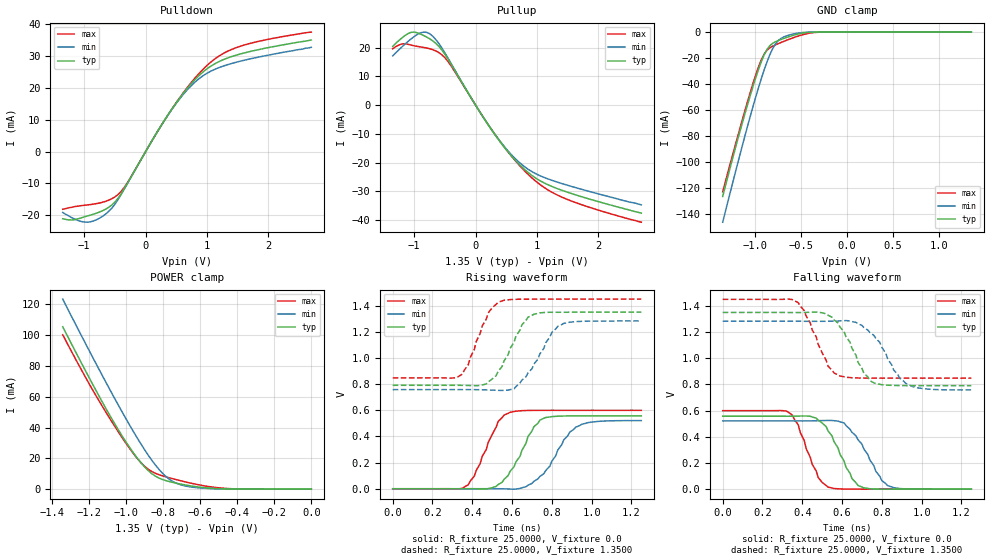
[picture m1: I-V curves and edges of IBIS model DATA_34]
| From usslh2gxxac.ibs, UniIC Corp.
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|When TDQS is enabled, NU_TDQS is a output with terminal resistance;
|When TDQS is disabled, NU_TDQS is a DM;
|   Model DATA_34
[Model]  DATA_34
Model_type I/O
Polarity   Non-Inverting
Enable   Active-High
Vinl =   0.54000000V
Vinh =   0.81000000V
Vmeas =   0.67500000V
Rref =   25.00000000
Vref =   0.67500000V
C_comp   1.6290pF   1.6100pF   1.6540pF
[Temperature Range]   25.0000   95.0000   0.0
[Voltage Range]   1.3500V   1.2830V   1.4500V
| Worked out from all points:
|   slope of the pulldown table from 0 to 0.203 V, typ, clamps not added: 30.6 ohm
|   slope of the pullup table from 0 to 0.203 V, typ, clamps not added: 29.9 ohm
|   GND clamp passes 1 mA (typ) near -0.50 V on its own axis
|   POWER clamp passes 1 mA (typ) near -0.58 V on its own axis
|   rising waveform, R_fixture 25.0000, V_fixture 0.0: 20-80 % time 118ps typ, 135ps min, 107ps max; typ from 0 V to 0.557 V
|   rising waveform, R_fixture 25.0000, V_fixture 1.3500: 20-80 % time 113ps typ, 123ps min, 93.4ps max; typ from 0.791 V to 1.35 V
|   falling waveform, R_fixture 25.0000, V_fixture 0.0: 20-80 % time 113ps typ, 123ps min, 92ps max; typ from 0.557 V to 0 V
|   falling waveform, R_fixture 25.0000, V_fixture 1.3500: 20-80 % time 116ps typ, 127ps min, 106ps max; typ from 1.35 V to 0.791 V
[Pulldown]
|Voltage   I(typ)   I(min)   I(max)
-1.35V    -21.1mA    -19.1mA    -18.1mA
-1.2V     -21.48mA   -20.8mA    -17.48mA
-950mV    -20.24mA   -22.17mA   -16.75mA
-600mV    -17.48mA   -18.77mA   -15.25mA
-350mV    -11.73mA   -11.85mA   -11.32mA
150mV     4.943mA    4.94mA     4.909mA
450mV     14mA       13.86mA    14.02mA
750mV     21.51mA    20.87mA    21.88mA
1V        26.03mA    24.64mA    27.09mA
1.25V     28.79mA    26.8mA     30.69mA
1.55V     30.74mA    28.48mA    33.18mA
2.7V      35.1mA     32.8mA     37.59mA
[Pullup]
|Voltage   I(typ)   I(min)   I(max)
-1.35V    20.4mA     17.1mA     19.6mA
-1.2V     23.38mA    20.25mA    21.28mA
-1.05V    25.31mA    23.05mA    20.88mA
-900mV    24.74mA    25.1mA     20.24mA
-750mV    23.1mA     24.86mA    19.62mA
-600mV    20.47mA    21.48mA    18.29mA
-450mV    16.03mA    16.38mA    15.2mA
250mV     -8.265mA   -8.209mA   -8.157mA
750mV     -21.44mA   -20.63mA   -21.8mA
1.05V     -26.3mA    -24.57mA   -27.64mA
1.4V      -29.59mA   -27.25mA   -31.96mA
2.7V      -37.6mA    -34.7mA    -40.73mA
[GND_clamp]
|Voltage   I(typ)   I(min)   I(max)
-1.35V    -126.6mA   -146.4mA   -123mA
-1.23V    -94.01mA   -112.8mA   -91.37mA
-1.14V    -70.71mA   -88.3mA    -68.32mA
-1.05V    -48.66mA   -64.66mA   -46.23mA
-960mV    -28.53mA   -42.51mA   -26.55mA
-900mV    -17.55mA   -29.16mA   -16.95mA
-840mV    -10.62mA   -17.72mA   -12.2mA
-780mV    -7.577mA   -9.433mA   -9.942mA
-720mV    -5.772mA   -5.033mA   -8.117mA
-540mV    -1.645mA   -864.3uA   -3.292mA
-330mV    -28.04uA   -10.8uA    -188.4uA
1.35V     3.66nA     11.73nA    27.08nA
[POWER_clamp]
|Voltage   I(typ)   I(min)   I(max)
-1.34V    105.5mA    123.5mA    100.3mA
-1.16V    63.99mA    81.44mA    60.61mA
-1.06V    42.52mA    58.94mA    40.95mA
-980mV    27.22mA    41.75mA    26.56mA
-920mV    17.45mA    29.69mA    17.42mA
-880mV    12.18mA    22.27mA    13mA
-840mV    8.415mA    15.63mA    10.28mA
-780mV    5.408mA    7.848mA    7.861mA
-700mV    3.206mA    2.693mA    5.332mA
-600mV    1.29mA     794.5uA    2.681mA
-420mV    69.47uA    44.47uA    238.7uA
0V        3.66nA     5.436nA    31.95nA
[Ramp]
| variable   typ   min   max
dV/dt_r  0.3343/0.1169n   0.3127/0.1346n   0.3598/99.9209p
dV/dt_f  0.3356/0.1137n   0.3152/0.1290n   0.3613/98.2845p
R_load = 25.0000
[Rising Waveform]
R_fixture= 25.0000
V_fixture= 0.0
V_fixture_min= 0.0
V_fixture_max= 0.0
|time   V(typ)   V(min)   V(max)
0s        0V         0V         0V
380ps     250uV      20.21uV    30.66mV
410ps     117.4uV    74.84uV    95.57mV
530ps     32.08mV    9.552uV    513.7mV
590ps     132.8mV    -2.345mV   584.5mV
710ps     474.8mV    56.97mV    599.1mV
760ps     539.1mV    115.7mV    599.5mV
860ps     556.1mV    373.5mV    599.6mV
920ps     557mV      470.3mV    599.6mV
1.25ns    557.2mV    521.1mV    599.6mV
[Rising Waveform]
R_fixture= 25.0000
V_fixture= 1.3500
V_fixture_min= 1.2830
V_fixture_max= 1.4500
|time   V(typ)   V(min)   V(max)
0s        790.7mV    757.6mV    847.8mV
350ps     790.5mV    757.7mV    876.5mV
380ps     789.5mV    757.7mV    948.2mV
480ps     816.6mV    755mV      1.344V
520ps     864.6mV    753mV      1.41V
560ps     977.9mV    752mV      1.441V
610ps     1.12V      763.8mV    1.448V
680ps     1.311V     884.7mV    1.449V
830ps     1.349V     1.242V     1.45V
1.25ns    1.35V      1.283V     1.45V
[Falling Waveform]
R_fixture= 25.0000
V_fixture= 0.0
V_fixture_min= 0.0
V_fixture_max= 0.0
|time   V(typ)   V(min)   V(max)
0s        557.2mV    521.1mV    599.6mV
350ps     557.3mV    521mV      566.3mV
380ps     558mV      520.9mV    490.9mV
480ps     527.4mV    523.2mV    90.02mV
530ps     444.9mV    524.9mV    15.71mV
610ps     216mV      506mV      935.2uV
650ps     80.92mV    434.4mV    178.7uV
710ps     9.833mV    305.7mV    19.12uV
830ps     108.3uV    26.34mV    0V
1.25ns    0V         0V         0V
[Falling Waveform]
R_fixture= 25.0000
V_fixture= 1.3500
V_fixture_min= 1.2830
V_fixture_max= 1.4500
|time   V(typ)   V(min)   V(max)
0s        1.35V      1.283V     1.45V
380ps     1.349V     1.283V     1.424V
440ps     1.351V     1.282V     1.271V
530ps     1.328V     1.283V     939.2mV
590ps     1.237V     1.286V     864.4mV
710ps     885.4mV    1.234V     848.3mV
760ps     812.2mV    1.175V     847.9mV
860ps     792.3mV    909.5mV    847.8mV
920ps     791mV      808mV      847.8mV
1.25ns    790.7mV    757.7mV    847.8mV
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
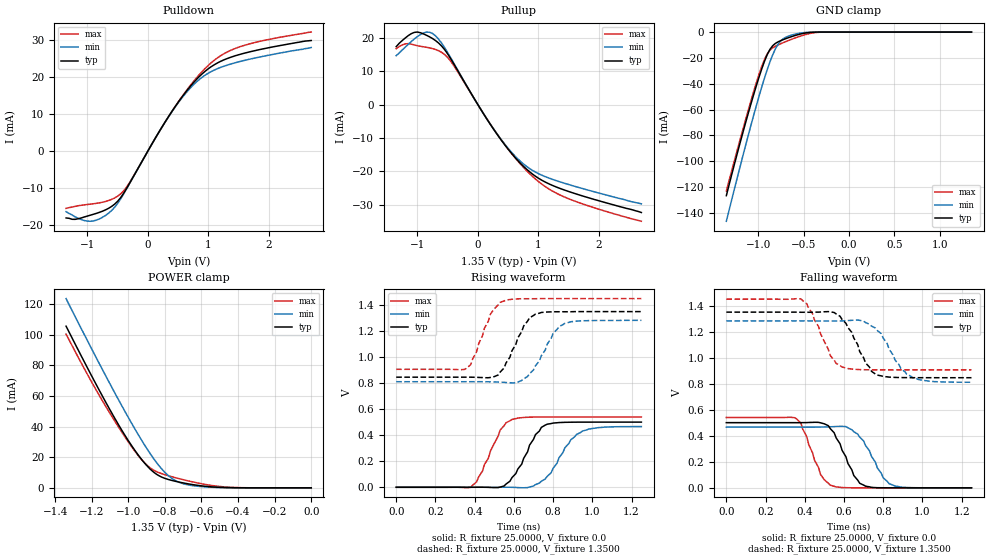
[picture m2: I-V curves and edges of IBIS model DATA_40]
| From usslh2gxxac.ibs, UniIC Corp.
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|   Model DATA_40
[Model]  DATA_40
Model_type I/O
Polarity   Non-Inverting
Enable   Active-High
Vinl =   0.54000000V
Vinh =   0.81000000V
Vmeas =   0.67500000V
Rref =   25.00000000
Vref =   0.67500000V
C_comp   1.6290pF   1.6100pF   1.6540pF
[Temperature Range]   25.0000   95.0000   0.0
[Voltage Range]   1.3500V   1.2830V   1.4500V
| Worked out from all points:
|   slope of the pulldown table from 0 to 0.203 V, typ, clamps not added: 35.6 ohm
|   slope of the pullup table from 0 to 0.203 V, typ, clamps not added: 34.8 ohm
|   GND clamp passes 1 mA (typ) near -0.50 V on its own axis
|   POWER clamp passes 1 mA (typ) near -0.58 V on its own axis
|   rising waveform, R_fixture 25.0000, V_fixture 0.0: 20-80 % time 102ps typ, 120ps min, 95.7ps max; typ from 0 V to 0.501 V
|   rising waveform, R_fixture 25.0000, V_fixture 1.3500: 20-80 % time 97.2ps typ, 102ps min, 85.6ps max; typ from 0.846 V to 1.35 V
|   falling waveform, R_fixture 25.0000, V_fixture 0.0: 20-80 % time 93ps typ, 104ps min, 82.9ps max; typ from 0.501 V to 0 V
|   falling waveform, R_fixture 25.0000, V_fixture 1.3500: 20-80 % time 103ps typ, 113ps min, 92.4ps max; typ from 1.35 V to 0.846 V
[Pulldown]
|Voltage   I(typ)   I(min)   I(max)
-1.35V    -18.1mA    -16.4mA    -15.5mA
-1.2V     -18.48mA   -17.8mA    -14.96mA
-950mV    -17.36mA   -19mA      -14.36mA
-600mV    -15mA      -16.12mA   -13.08mA
-350mV    -10.09mA   -10.2mA    -9.729mA
150mV     4.251mA    4.248mA    4.221mA
450mV     12.04mA    11.91mA    12.05mA
750mV     18.48mA    17.93mA    18.8mA
1V        22.35mA    21.14mA    23.26mA
1.25V     24.7mA     22.99mA    26.34mA
1.55V     26.36mA    24.42mA    28.46mA
2.7V      30mA       28.1mA     32.29mA
[Pullup]
|Voltage   I(typ)   I(min)   I(max)
-1.35V    17.4mA     14.7mA     16.8mA
-1.2V     20mA       17.25mA    18.24mA
-1.05V    21.68mA    19.73mA    17.91mA
-900mV    21.23mA    21.49mA    17.36mA
-750mV    19.83mA    21.34mA    16.82mA
-600mV    17.59mA    18.47mA    15.7mA
-450mV    13.79mA    14.09mA    13.06mA
250mV     -7.107mA   -7.058mA   -7.014mA
750mV     -18.41mA   -17.72mA   -18.73mA
1.05V     -22.57mA   -21.08mA   -23.73mA
1.4V      -25.38mA   -23.37mA   -27.42mA
2.7V      -32.3mA    -29.7mA    -34.93mA
[GND_clamp]
|Voltage   I(typ)   I(min)   I(max)
-1.35V    -126.6mA   -146.4mA   -123mA
-1.23V    -94.01mA   -112.8mA   -91.37mA
-1.14V    -70.71mA   -88.3mA    -68.32mA
-1.05V    -48.66mA   -64.66mA   -46.23mA
-960mV    -28.53mA   -42.51mA   -26.55mA
-900mV    -17.55mA   -29.16mA   -16.95mA
-840mV    -10.62mA   -17.72mA   -12.2mA
-780mV    -7.577mA   -9.433mA   -9.942mA
-720mV    -5.772mA   -5.033mA   -8.117mA
-540mV    -1.645mA   -864.3uA   -3.292mA
-330mV    -28.04uA   -10.8uA    -188.4uA
1.35V     3.66nA     11.73nA    27.08nA
[POWER_clamp]
|Voltage   I(typ)   I(min)   I(max)
-1.34V    105.5mA    123.5mA    100.3mA
-1.16V    63.99mA    81.44mA    60.61mA
-1.06V    42.52mA    58.94mA    40.95mA
-980mV    27.22mA    41.75mA    26.56mA
-920mV    17.45mA    29.69mA    17.42mA
-880mV    12.18mA    22.27mA    13mA
-840mV    8.415mA    15.63mA    10.28mA
-780mV    5.408mA    7.848mA    7.861mA
-700mV    3.206mA    2.693mA    5.332mA
-600mV    1.29mA     794.5uA    2.681mA
-420mV    69.47uA    44.47uA    238.7uA
0V        3.66nA     5.436nA    31.95nA
[Ramp]
| variable   typ   min   max
dV/dt_r  0.3005/0.1058n   0.2799/0.1203n   0.3242/93.0091p
dV/dt_f  0.3023/0.1041n   0.2831/0.1145n   0.3261/91.8068p
R_load = 25.0000
[Rising Waveform]
R_fixture= 25.0000
V_fixture= 0.0
V_fixture_min= 0.0
V_fixture_max= 0.0
|time   V(typ)   V(min)   V(max)
0s        0V         0V         0V
380ps     95.35uV    -9.554uV   -413.5uV
440ps     330.8uV    55.67uV    125.3mV
530ps     1.559mV    374.3uV    439.9mV
590ps     73.89mV    -392.8uV   521mV
710ps     404.5mV    19.98mV    539.7mV
770ps     484.8mV    84.21mV    540.3mV
890ps     500.1mV    365.1mV    540.3mV
950ps     500.7mV    432.1mV    540.3mV
1.25ns    500.8mV    466.5mV    540.3mV
[Rising Waveform]
R_fixture= 25.0000
V_fixture= 1.3500
V_fixture_min= 1.2830
V_fixture_max= 1.4500
|time   V(typ)   V(min)   V(max)
0s        846.1mV    811.2mV    906.5mV
350ps     846.3mV    811.2mV    906.3mV
380ps     846.1mV    811.3mV    942.6mV
480ps     844.1mV    810.3mV    1.329V
560ps     955.6mV    805.1mV    1.439V
650ps     1.24V      834mV      1.449V
710ps     1.331V     934mV      1.449V
800ps     1.349V     1.183V     1.45V
860ps     1.349V     1.26V      1.45V
1.25ns    1.35V      1.283V     1.45V
[Falling Waveform]
R_fixture= 25.0000
V_fixture= 0.0
V_fixture_min= 0.0
V_fixture_max= 0.0
|time   V(typ)   V(min)   V(max)
0s        500.8mV    466.5mV    540.3mV
350ps     500.7mV    466.5mV    538.4mV
380ps     500.7mV    466.4mV    498.2mV
480ps     499.8mV    467.1mV    103.9mV
560ps     383.6mV    471.3mV    6.777mV
650ps     94.15mV    431.4mV    277.6uV
710ps     12.71mV    324.5mV    32.69uV
800ps     404.9uV    76.66mV    0V
860ps     61.5uV     13.66mV    0V
1.25ns    0V         0V         0V
[Falling Waveform]
R_fixture= 25.0000
V_fixture= 1.3500
V_fixture_min= 1.2830
V_fixture_max= 1.4500
|time   V(typ)   V(min)   V(max)
0s        1.35V      1.283V     1.45V
380ps     1.349V     1.283V     1.452V
440ps     1.349V     1.283V     1.337V
530ps     1.353V     1.282V     1.016V
590ps     1.294V     1.283V     928.6mV
710ps     959.3mV    1.27V      907.3mV
770ps     866.2mV    1.209V     906.6mV
890ps     847.2mV    916.4mV    906.5mV
950ps     846.4mV    846.7mV    906.5mV
1.25ns    846.1mV    811.3mV    906.5mV
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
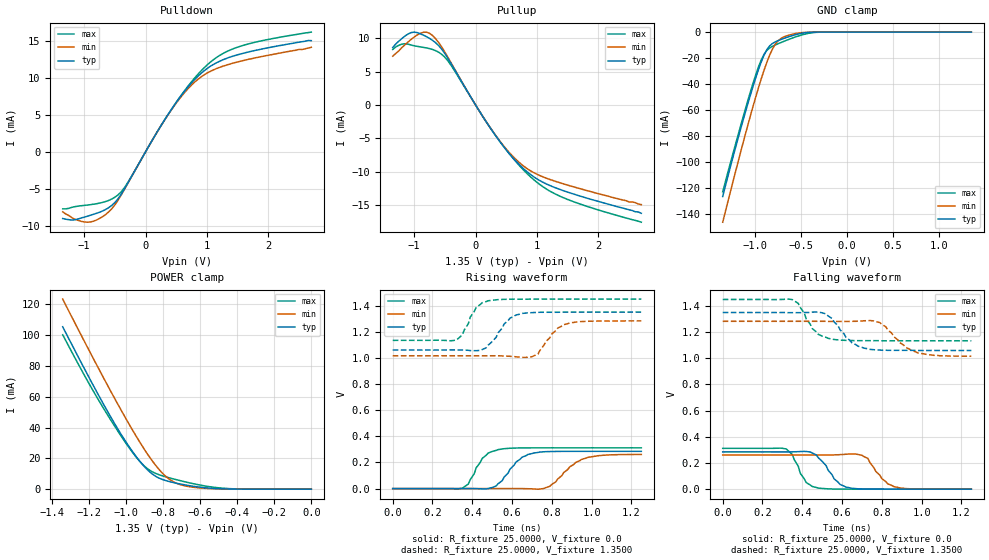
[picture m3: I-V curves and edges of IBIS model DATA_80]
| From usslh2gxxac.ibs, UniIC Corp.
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|   Model DATA_80
[Model]  DATA_80
Model_type I/O
Polarity   Non-Inverting
Enable   Active-High
Vinl =   0.54000000V
Vinh =   0.81000000V
Vmeas =   0.67500000V
Rref =   25.00000000
Vref =   0.67500000V
C_comp   1.6290pF   1.6100pF   1.6540pF
[Temperature Range]   25.0000   95.0000   0.0
[Voltage Range]   1.3500V   1.2830V   1.4500V
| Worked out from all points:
|   slope of the pulldown table from 0 to 0.203 V, typ, clamps not added: 70.5 ohm
|   slope of the pullup table from 0 to 0.203 V, typ, clamps not added: 69 ohm
|   GND clamp passes 1 mA (typ) near -0.50 V on its own axis
|   POWER clamp passes 1 mA (typ) near -0.58 V on its own axis
|   rising waveform, R_fixture 25.0000, V_fixture 0.0: 20-80 % time 95.1ps typ, 114ps min, 77.4ps max; typ from 0 V to 0.285 V
|   rising waveform, R_fixture 25.0000, V_fixture 1.3500: 20-80 % time 88.7ps typ, 85.8ps min, 64.4ps max; typ from 1.06 V to 1.35 V
|   falling waveform, R_fixture 25.0000, V_fixture 0.0: 20-80 % time 88.5ps typ, 85ps min, 62.1ps max; typ from 0.285 V to 0 V
|   falling waveform, R_fixture 25.0000, V_fixture 1.3500: 20-80 % time 95ps typ, 116ps min, 82ps max; typ from 1.35 V to 1.06 V
[Pulldown]
|Voltage   I(typ)   I(min)   I(max)
-1.35V    -9mA       -8.1mA     -7.7mA
-1.2V     -9.22mA    -8.9mA     -7.49mA
-950mV    -8.7mA     -9.5mA     -7.19mA
-800mV    -8.305mA   -9.21mA    -7.01mA
-600mV    -7.532mA   -8.104mA   -6.562mA
-350mV    -5.095mA   -5.151mA   -4.906mA
150mV     2.146mA    2.145mA    2.131mA
450mV     6.069mA    6.003mA    6.077mA
750mV     9.3mA      9.014mA    9.466mA
1V        11.22mA    10.61mA    11.69mA
1.5V      13.09mA    12.12mA    14.12mA
2.7V      15mA       14.1mA     16.15mA
[Pullup]
|Voltage   I(typ)   I(min)   I(max)
-1.35V    8.6mA      7.3mA      8.3mA
-1.2V     9.94mA     8.59mA     9.1mA
-1.05V    10.82mA    9.81mA     8.97mA
-900mV    10.64mA    10.72mA    8.69mA
-750mV    9.959mA    10.72mA    8.43mA
-600mV    8.86mA     9.316mA    7.879mA
-450mV    6.969mA    7.125mA    6.59mA
250mV     -3.587mA   -3.562mA   -3.54mA
750mV     -9.264mA   -8.906mA   -9.428mA
1.05V     -11.33mA   -10.57mA   -11.92mA
1.4V      -12.72mA   -11.71mA   -13.75mA
2.7V      -16.2mA    -14.9mA    -17.53mA
[GND_clamp]
|Voltage   I(typ)   I(min)   I(max)
-1.35V    -126.6mA   -146.4mA   -123mA
-1.23V    -94.01mA   -112.8mA   -91.37mA
-1.14V    -70.71mA   -88.3mA    -68.32mA
-1.05V    -48.66mA   -64.66mA   -46.23mA
-960mV    -28.53mA   -42.51mA   -26.55mA
-900mV    -17.55mA   -29.16mA   -16.95mA
-840mV    -10.62mA   -17.72mA   -12.2mA
-780mV    -7.577mA   -9.433mA   -9.942mA
-720mV    -5.772mA   -5.033mA   -8.117mA
-540mV    -1.645mA   -864.3uA   -3.292mA
-330mV    -28.04uA   -10.8uA    -188.4uA
1.35V     3.66nA     11.73nA    27.08nA
[POWER_clamp]
|Voltage   I(typ)   I(min)   I(max)
-1.34V    105.5mA    123.5mA    100.3mA
-1.16V    63.99mA    81.44mA    60.61mA
-1.06V    42.52mA    58.94mA    40.95mA
-980mV    27.22mA    41.75mA    26.56mA
-920mV    17.45mA    29.69mA    17.42mA
-880mV    12.18mA    22.27mA    13mA
-840mV    8.415mA    15.63mA    10.28mA
-780mV    5.408mA    7.848mA    7.861mA
-700mV    3.206mA    2.693mA    5.332mA
-600mV    1.29mA     794.5uA    2.681mA
-420mV    69.47uA    44.47uA    238.7uA
0V        3.66nA     5.436nA    31.95nA
[Ramp]
| variable   typ   min   max
dV/dt_r  0.1711/95.8702p   0.1568/0.1150n   0.1871/74.5281p
dV/dt_f  0.1740/97.5000p   0.1602/0.1134n   0.1896/78.8115p
R_load = 25.0000
[Rising Waveform]
R_fixture= 25.0000
V_fixture= 0.0
V_fixture_min= 0.0
V_fixture_max= 0.0
|time   V(typ)   V(min)   V(max)
0s        0V         0V         0V
350ps     147.1uV    0V         2.732mV
380ps     308.3uV    -1.668uV   34.42mV
450ps     -2.449mV   -13.34uV   231.4mV
530ps     37.36mV    89.21uV    298.3mV
620ps     203.4mV    449.6uV    310.4mV
710ps     272.5mV    -3.187mV   311.8mV
790ps     283.4mV    17.6mV     311.9mV
980ps     285mV      238.6mV    311.9mV
1.25ns    285.1mV    261.3mV    311.9mV
[Rising Waveform]
R_fixture= 25.0000
V_fixture= 1.3500
V_fixture_min= 1.2830
V_fixture_max= 1.4500
|time   V(typ)   V(min)   V(max)
0s        1.06V      1.016V     1.134V
320ps     1.061V     1.016V     1.136V
350ps     1.06V      1.016V     1.176V
420ps     1.055V     1.016V     1.387V
480ps     1.097V     1.016V     1.437V
590ps     1.304V     1.012V     1.449V
650ps     1.34V      1.004V     1.449V
730ps     1.348V     1.028V     1.45V
860ps     1.35V      1.254V     1.45V
1.25ns    1.35V      1.283V     1.45V
[Falling Waveform]
R_fixture= 25.0000
V_fixture= 0.0
V_fixture_min= 0.0
V_fixture_max= 0.0
|time   V(typ)   V(min)   V(max)
0s        285.1mV    261.4mV    311.9mV
320ps     284.8mV    261.4mV    307.1mV
350ps     285.2mV    261.4mV    264.4mV
420ps     288mV      261.3mV    50.49mV
480ps     241.1mV    261mV      8.563mV
620ps     15.58mV    267.3mV    160.2uV
730ps     785.6uV    235.2mV    6.833uV
800ps     64.2uV     80.46mV    0V
860ps     11.7uV     19.72mV    0V
1.25ns    0V         0V         0V
[Falling Waveform]
R_fixture= 25.0000
V_fixture= 1.3500
V_fixture_min= 1.2830
V_fixture_max= 1.4500
|time   V(typ)   V(min)   V(max)
0s        1.35V      1.283V     1.45V
350ps     1.349V     1.283V     1.449V
380ps     1.349V     1.283V     1.42V
450ps     1.353V     1.283V     1.228V
500ps     1.348V     1.283V     1.17V
550ps     1.305V     1.282V     1.147V
650ps     1.118V     1.283V     1.136V
760ps     1.066V     1.286V     1.135V
980ps     1.06V      1.042V     1.134V
1.25ns    1.06V      1.016V     1.134V
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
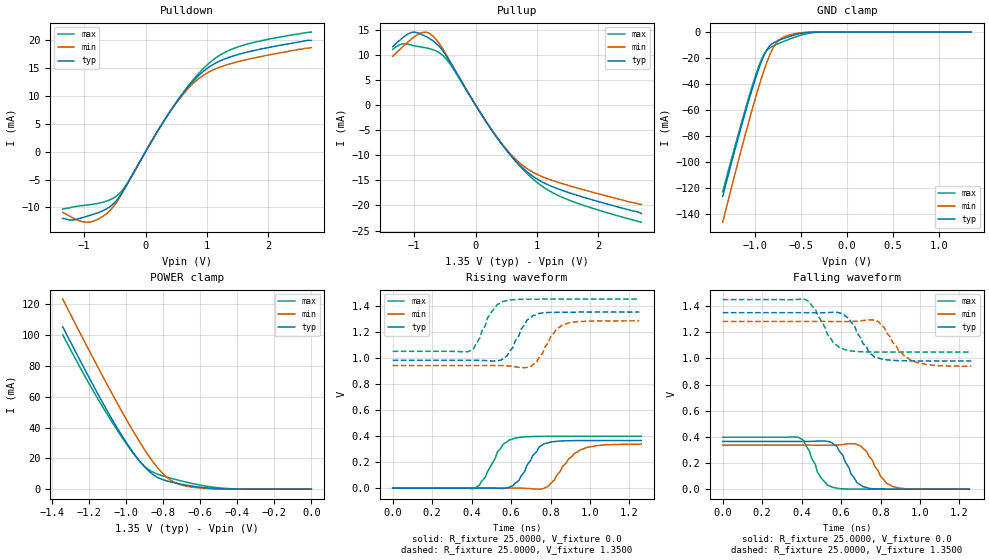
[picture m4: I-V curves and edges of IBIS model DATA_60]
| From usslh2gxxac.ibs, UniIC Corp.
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|   Model DATA_60
[Model]  DATA_60
Model_type I/O
Polarity   Non-Inverting
Enable   Active-High
Vinl =   0.54000000V
Vinh =   0.81000000V
Vmeas =   0.67500000V
Rref =   25.00000000
Vref =   0.67500000V
C_comp   1.6290pF   1.6100pF   1.6540pF
[Temperature Range]   25.0000   95.0000   0.0
[Voltage Range]   1.3500V   1.2830V   1.4500V
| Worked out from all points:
|   slope of the pulldown table from 0 to 0.203 V, typ, clamps not added: 53.1 ohm
|   slope of the pullup table from 0 to 0.203 V, typ, clamps not added: 51.9 ohm
|   GND clamp passes 1 mA (typ) near -0.50 V on its own axis
|   POWER clamp passes 1 mA (typ) near -0.58 V on its own axis
|   rising waveform, R_fixture 25.0000, V_fixture 0.0: 20-80 % time 89.5ps typ, 106ps min, 85.6ps max; typ from 0 V to 0.365 V
|   rising waveform, R_fixture 25.0000, V_fixture 1.3500: 20-80 % time 80.5ps typ, 82.1ps min, 79.3ps max; typ from 0.98 V to 1.35 V
|   falling waveform, R_fixture 25.0000, V_fixture 0.0: 20-80 % time 81.1ps typ, 84.2ps min, 74ps max; typ from 0.365 V to 0 V
|   falling waveform, R_fixture 25.0000, V_fixture 1.3500: 20-80 % time 86.7ps typ, 107ps min, 85.1ps max; typ from 1.35 V to 0.98 V
[Pulldown]
|Voltage   I(typ)   I(min)   I(max)
-1.35V    -12mA      -10.9mA    -10.3mA
-1.2V     -12.29mA   -11.8mA    -9.98mA
-950mV    -11.59mA   -12.67mA   -9.58mA
-600mV    -10.03mA   -10.79mA   -8.732mA
-350mV    -6.771mA   -6.844mA   -6.524mA
150mV     2.852mA    2.85mA     2.832mA
450mV     8.069mA    7.982mA    8.079mA
750mV     12.37mA    12mA       12.59mA
1V        14.94mA    14.13mA    15.56mA
1.25V     16.49mA    15.34mA    17.6mA
1.55V     17.59mA    16.3mA     18.99mA
2.7V      20mA       18.7mA     21.49mA
[Pullup]
|Voltage   I(typ)   I(min)   I(max)
-1.35V    11.6mA     9.7mA      11.1mA
-1.2V     13.28mA    11.45mA    12.15mA
-1.05V    14.44mA    13.1mA     11.95mA
-900mV    14.18mA    14.31mA    11.58mA
-750mV    13.26mA    14.27mA    11.23mA
-600mV    11.78mA    12.39mA    10.5mA
-450mV    9.259mA    9.464mA    8.761mA
250mV     -4.768mA   -4.734mA   -4.705mA
750mV     -12.33mA   -11.85mA   -12.54mA
1.05V     -15.08mA   -14.08mA   -15.87mA
1.35V     -16.72mA   -15.41mA   -18.04mA
2.7V      -21.6mA    -19.8mA    -23.33mA
[GND_clamp]
|Voltage   I(typ)   I(min)   I(max)
-1.35V    -126.6mA   -146.4mA   -123mA
-1.23V    -94.01mA   -112.8mA   -91.37mA
-1.14V    -70.71mA   -88.3mA    -68.32mA
-1.05V    -48.66mA   -64.66mA   -46.23mA
-960mV    -28.53mA   -42.51mA   -26.55mA
-900mV    -17.55mA   -29.16mA   -16.95mA
-840mV    -10.62mA   -17.72mA   -12.2mA
-780mV    -7.577mA   -9.433mA   -9.942mA
-720mV    -5.772mA   -5.033mA   -8.117mA
-540mV    -1.645mA   -864.3uA   -3.292mA
-330mV    -28.04uA   -10.8uA    -188.4uA
1.35V     3.66nA     11.73nA    27.08nA
[POWER_clamp]
|Voltage   I(typ)   I(min)   I(max)
-1.34V    105.5mA    123.5mA    100.3mA
-1.16V    63.99mA    81.44mA    60.61mA
-1.06V    42.52mA    58.94mA    40.95mA
-980mV    27.22mA    41.75mA    26.56mA
-920mV    17.45mA    29.69mA    17.42mA
-880mV    12.18mA    22.27mA    13mA
-840mV    8.415mA    15.63mA    10.28mA
-780mV    5.408mA    7.848mA    7.861mA
-700mV    3.206mA    2.693mA    5.332mA
-600mV    1.29mA     794.5uA    2.681mA
-420mV    69.47uA    44.47uA    238.7uA
0V        3.66nA     5.436nA    31.95nA
[Ramp]
| variable   typ   min   max
dV/dt_r  0.2191/91.3875p   0.2020/0.1080n   0.2384/81.1256p
dV/dt_f  0.2217/91.5243p   0.2057/0.1059n   0.2406/82.7241p
R_load = 25.0000
[Rising Waveform]
R_fixture= 25.0000
V_fixture= 0.0
V_fixture_min= 0.0
V_fixture_max= 0.0
|time   V(typ)   V(min)   V(max)
0s        0V         0V         0V
410ps     26.87uV    -4.966uV   -4.273mV
470ps     313.1uV    -20.2uV    84.25mV
530ps     -1.175mV   82.15uV    275.2mV
580ps     524.6uV    386.4uV    355.9mV
640ps     59.46mV    491.2uV    388.2mV
710ps     251.2mV    -5.999mV   396mV
760ps     332.9mV    -5.287mV   397mV
950ps     364.8mV    292.9mV    397.3mV
1.26ns    365.2mV    337.3mV    397.3mV
[Rising Waveform]
R_fixture= 25.0000
V_fixture= 1.3500
V_fixture_min= 1.2830
V_fixture_max= 1.4500
|time   V(typ)   V(min)   V(max)
0s        980.5mV    940mV      1.049V
390ps     980.7mV    940mV      1.052V
440ps     980.1mV    940.1mV    1.148V
500ps     975.5mV    940.5mV    1.35V
590ps     1.044V     936.3mV    1.442V
680ps     1.288V     925.9mV    1.449V
740ps     1.339V     998.6mV    1.449V
800ps     1.348V     1.162V     1.45V
860ps     1.349V     1.251V     1.45V
1.25ns    1.35V      1.283V     1.45V
[Falling Waveform]
R_fixture= 25.0000
V_fixture= 0.0
V_fixture_min= 0.0
V_fixture_max= 0.0
|time   V(typ)   V(min)   V(max)
0s        365.2mV    336.7mV    397.3mV
380ps     365.1mV    336.7mV    398.2mV
410ps     365mV      336.7mV    373.2mV
500ps     368.5mV    336.2mV    82.96mV
560ps     345.3mV    336.8mV    12.1mV
680ps     50.01mV    341.2mV    269.9uV
710ps     20.31mV    312.6mV    103.9uV
800ps     868uV      97.17mV    3.253uV
860ps     145.1uV    20.6mV     0V
1.25ns    0V         3.694uV    0V
[Falling Waveform]
R_fixture= 25.0000
V_fixture= 1.3500
V_fixture_min= 1.2830
V_fixture_max= 1.4500
|time   V(typ)   V(min)   V(max)
0s        1.35V      1.283V     1.45V
420ps     1.35V      1.283V     1.449V
470ps     1.349V     1.283V     1.375V
590ps     1.349V     1.282V     1.084V
640ps     1.306V     1.282V     1.06V
760ps     1.022V     1.294V     1.049V
820ps     992.3mV    1.233V     1.049V
890ps     982.8mV    1.064V     1.049V
950ps     981.1mV    988.9mV    1.049V
1.26ns    980.5mV    940.1mV    1.049V
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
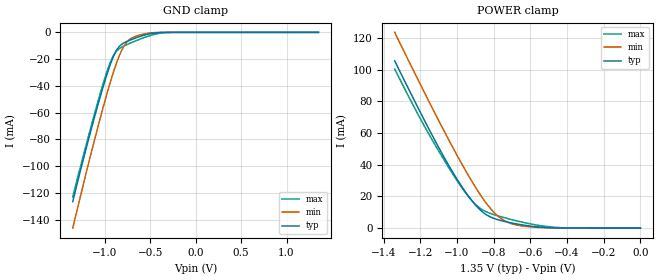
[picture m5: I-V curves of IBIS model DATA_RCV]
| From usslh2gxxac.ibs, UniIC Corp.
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|   Model DATA_RCV
[Model]  DATA_RCV
Model_type Input
Vinl =   0.54000000V
Vinh =   0.81000000V
C_comp   1.6290pF   1.6100pF   1.6540pF
[Temperature Range]   25.0000   95.0000   0.0
[Voltage Range]   1.3500V   1.2830V   1.4500V
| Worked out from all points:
|   GND clamp passes 1 mA (typ) near -0.50 V on its own axis
|   POWER clamp passes 1 mA (typ) near -0.58 V on its own axis
[GND_clamp]
|Voltage   I(typ)   I(min)   I(max)
-1.35V    -126.6mA   -146.4mA   -123mA
-1.23V    -94.01mA   -112.8mA   -91.37mA
-1.14V    -70.71mA   -88.3mA    -68.32mA
-1.05V    -48.66mA   -64.66mA   -46.23mA
-960mV    -28.53mA   -42.51mA   -26.55mA
-900mV    -17.55mA   -29.16mA   -16.95mA
-840mV    -10.62mA   -17.72mA   -12.2mA
-780mV    -7.577mA   -9.433mA   -9.942mA
-720mV    -5.772mA   -5.033mA   -8.117mA
-540mV    -1.645mA   -864.3uA   -3.292mA
-330mV    -28.04uA   -10.8uA    -188.4uA
1.35V     3.66nA     11.73nA    27.08nA
[POWER_clamp]
|Voltage   I(typ)   I(min)   I(max)
-1.34V    105.5mA    123.5mA    100.3mA
-1.16V    63.99mA    81.44mA    60.61mA
-1.06V    42.52mA    58.94mA    40.95mA
-980mV    27.22mA    41.75mA    26.56mA
-920mV    17.45mA    29.69mA    17.42mA
-880mV    12.18mA    22.27mA    13mA
-840mV    8.415mA    15.63mA    10.28mA
-780mV    5.408mA    7.848mA    7.861mA
-700mV    3.206mA    2.693mA    5.332mA
-600mV    1.29mA     794.5uA    2.681mA
-420mV    69.47uA    44.47uA    238.7uA
0V        3.66nA     5.436nA    31.95nA
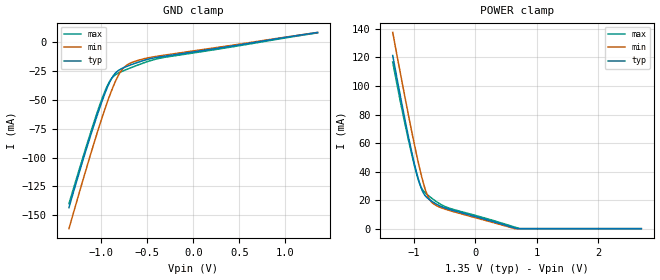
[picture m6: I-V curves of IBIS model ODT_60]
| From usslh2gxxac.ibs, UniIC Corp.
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|   Model ODT_60
[Model]  ODT_60
Model_type Input
Vinl =   0.54000000V
Vinh =   0.81000000V
C_comp   1.6290pF   1.6100pF   1.6540pF
[Temperature Range]   25.0000   95.0000   0.0
[Voltage Range]   1.3500V   1.2800V   1.4500V
[GND_clamp]
|Voltage   I(typ)   I(min)   I(max)
-1.35V    -143.4mA   -161.6mA   -140mA
-1.23V    -110.7mA   -128.2mA   -108.1mA
-1.14V    -87.26mA   -103.8mA   -84.75mA
-1.05V    -64.91mA   -80.22mA   -62.44mA
-960mV    -44.49mA   -58.01mA   -42.55mA
-900mV    -33.31mA   -44.54mA   -32.81mA
-840mV    -26.18mA   -32.93mA   -27.9mA
-780mV    -22.93mA   -24.4mA    -25.49mA
-720mV    -20.89mA   -19.73mA   -23.48mA
-570mV    -16.6mA    -15.05mA   -18.83mA
-330mV    -12.29mA   -11.4mA    -13.35mA
1.35V     8.47mA     8.53mA     8.122mA
[POWER_clamp]
|Voltage   I(typ)   I(min)   I(max)
-1.34V    121.4mA    137.6mA    116.8mA
-1.22V    94mA       110mA      90.09mA
-1.12V    72.01mA    87.54mA    69.28mA
-1.02V    51.59mA    65.83mA    50.06mA
-940mV    37.36mA    49.47mA    36.55mA
-880mV    28.83mA    38.26mA    29.22mA
-800mV    22.5mA     26.06mA    24.63mA
-740mV    20.27mA    20.35mA    22.47mA
-680mV    18.51mA    17.5mA     20.49mA
-420mV    13.53mA    12.79mA    14.36mA
675mV     0A         NA         NA
2.7V      0A         0A         0A
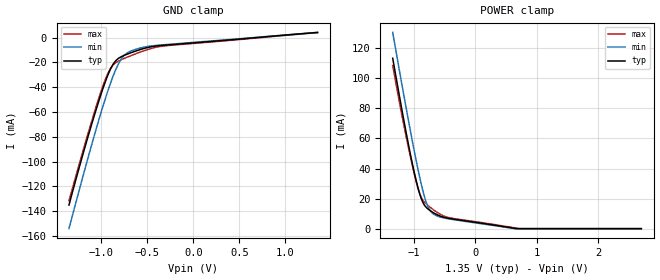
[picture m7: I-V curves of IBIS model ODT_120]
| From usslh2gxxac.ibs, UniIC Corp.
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|   Model ODT_120
[Model]  ODT_120
Model_type Input
Vinl =   0.54000000V
Vinh =   0.81000000V
C_comp   1.6290pF   1.6100pF   1.6540pF
[Temperature Range]   25.0000   95.0000   0.0
[Voltage Range]   1.3500V   1.2830V   1.4500V
[GND_clamp]
|Voltage   I(typ)   I(min)   I(max)
-1.35V    -135mA     -154mA     -131.5mA
-1.14V    -78.99mA   -96.1mA    -76.54mA
-1.02V    -49.74mA   -64.88mA   -47.34mA
-960mV    -36.51mA   -50.3mA    -34.55mA
-900mV    -25.43mA   -36.89mA   -24.88mA
-870mV    -21.31mA   -30.83mA   -21.92mA
-840mV    -18.4mA    -25.37mA   -20.05mA
-780mV    -15.26mA   -16.96mA   -17.72mA
-720mV    -13.34mA   -12.42mA   -15.8mA
-570mV    -9.41mA    -8.197mA   -11.43mA
-330mV    -6.169mA   -5.742mA   -6.779mA
1.35V     4.238mA    4.275mA    4.063mA
[POWER_clamp]
|Voltage   I(typ)   I(min)   I(max)
-1.34V    113.4mA    130.6mA    108.6mA
-1.22V    85.77mA    102.7mA    81.7mA
-1.12V    63.6mA     79.97mA    60.91mA
-1.02V    43.09mA    58.06mA    41.81mA
-940mV    28.93mA    41.56mA    28.38mA
-860mV    18.38mA    26.87mA    19.55mA
-800mV    14.34mA    18.1mA     16.6mA
-740mV    12.25mA    12.5mA     14.51mA
-680mV    10.64mA    9.841mA    12.63mA
-420mV    6.809mA    6.453mA    7.306mA
675mV     0A         NA         NA
2.7V      0A         0A         0A
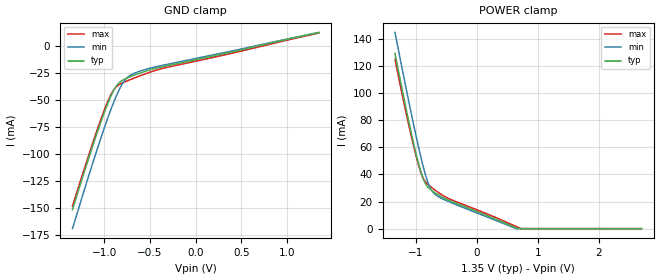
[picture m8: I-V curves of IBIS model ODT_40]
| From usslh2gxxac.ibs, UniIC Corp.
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|   Model ODT_40
[Model]  ODT_40
Model_type Input
Vinl =   0.54000000V
Vinh =   0.81000000V
C_comp   1.6290pF   1.6100pF   1.6540pF
[Temperature Range]   25.0000   95.0000   0.0
[Voltage Range]   1.3500V   1.2830V   1.4500V
[GND_clamp]
|Voltage   I(typ)   I(min)   I(max)
-1.35V    -151.8mA   -169.3mA   -148.5mA
-1.2V     -111.1mA   -127.9mA   -108.5mA
-1.11V    -87.88mA   -103.7mA   -85.33mA
-1.02V    -65.87mA   -80.5mA    -63.46mA
-960mV    -52.45mA   -65.86mA   -50.53mA
-900mV    -41.18mA   -52.33mA   -40.72mA
-870mV    -36.95mA   -46.18mA   -37.69mA
-810mV    -31.97mA   -35.83mA   -34.38mA
-750mV    -29.46mA   -29.14mA   -32.18mA
-660mV    -26.49mA   -24.63mA   -29.13mA
-450mV    -20.72mA   -19.34mA   -22.69mA
1.35V     12.7mA     12.8mA     12.18mA
[POWER_clamp]
|Voltage   I(typ)   I(min)   I(max)
-1.34V    129.3mA    144.8mA    125mA
-1.12V    80.44mA    95.24mA    77.65mA
-1.02V    60.08mA    73.74mA    58.31mA
-940mV    45.77mA    57.5mA     44.7mA
-880mV    37.14mA    46.35mA    37.32mA
-840mV    33.15mA    39.73mA    34.48mA
-800mV    30.66mA    34.12mA    32.65mA
-740mV    28.29mA    28.3mA     30.41mA
-680mV    26.36mA    25.27mA    28.35mA
-440mV    20.6mA     19.59mA    21.79mA
675mV     0A         NA         NA
2.7V      0A         0A         0A
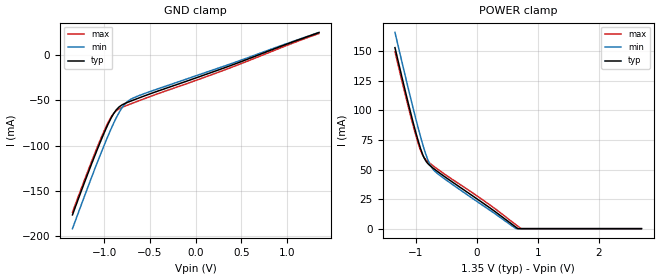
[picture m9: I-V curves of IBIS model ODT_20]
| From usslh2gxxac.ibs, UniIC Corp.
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|   Model ODT_20
[Model]  ODT_20
Model_type Input
Vinl =   0.54000000V
Vinh =   0.81000000V
C_comp   1.6290pF   1.6100pF   1.6540pF
[Temperature Range]   25.0000   95.0000   0.0
[Voltage Range]   1.3500V   1.2830V   1.4500V
[GND_clamp]
|Voltage   I(typ)   I(min)   I(max)
-1.35V    -176.9mA   -192.2mA   -174mA
-1.11V    -112.5mA   -127.1mA   -109.8mA
-1.02V    -90.01mA   -103.9mA   -87.59mA
-960mV    -76.29mA   -89.16mA   -74.45mA
-900mV    -64.72mA   -75.43mA   -64.43mA
-870mV    -60.35mA   -69.15mA   -61.28mA
-810mV    -55.06mA   -58.46mA   -57.73mA
-750mV    -52.21mA   -51.37mA   -55.28mA
-690mV    -49.83mA   -47.52mA   -52.94mA
-540mV    -44.11mA   -41.53mA   -47.18mA
300mV     -14.29mA   -12.27mA   -16.75mA
1.35V     25.34mA    25.54mA    24.31mA
[POWER_clamp]
|Voltage   I(typ)   I(min)   I(max)
-1.34V    153.2mA    166.1mA    149.8mA
-1.2V     122.7mA    135.4mA    119.4mA
-1.08V    97.49mA    109.8mA    94.63mA
-980mV    78mA       89.27mA    75.74mA
-920mV    67.71mA    77.67mA    66.24mA
-860mV    59.69mA    67.03mA    59.93mA
-780mV    54.02mA    55.69mA    55.82mA
-720mV    51.44mA    50.47mA    53.43mA
-640mV    48.29mA    46.49mA    50.34mA
200mV     18.16mA    16.15mA    20.67mA
674.9mV   0A         NA         NA
2.7V      0A         0A         0A
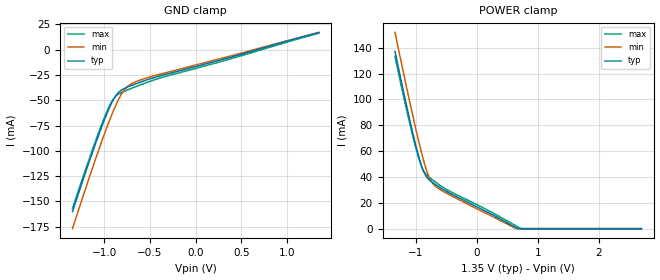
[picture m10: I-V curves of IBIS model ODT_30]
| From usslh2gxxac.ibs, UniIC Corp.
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|   Model ODT_30
[Model]  ODT_30
Model_type Input
Vinl =   0.54000000V
Vinh =   0.81000000V
C_comp   1.6290pF   1.6100pF   1.6540pF
[Temperature Range]   25.0000   95.0000   0.0
[Voltage Range]   1.3500V   1.2830V   1.4500V
[GND_clamp]
|Voltage   I(typ)   I(min)   I(max)
-1.35V    -160.1mA   -176.9mA   -157mA
-1.23V    -127.4mA   -143.8mA   -124.7mA
-1.11V    -96.08mA   -111.5mA   -93.49mA
-1.02V    -73.93mA   -88.3mA    -71.51mA
-960mV    -60.41mA   -73.63mA   -58.51mA
-900mV    -49.04mA   -60.04mA   -48.63mA
-870mV    -44.76mA   -53.85mA   -45.56mA
-810mV    -39.67mA   -43.38mA   -42.18mA
-750mV    -37.05mA   -36.56mA   -39.89mA
-660mV    -33.9mA    -31.82mA   -36.69mA
-480mV    -28.26mA   -26.43mA   -30.66mA
1.35V     16.92mA    17.06mA    16.22mA
[POWER_clamp]
|Voltage   I(typ)   I(min)   I(max)
-1.34V    137.3mA    151.9mA    133.3mA
-1.12V    88.86mA    102.9mA    86.01mA
-1.02V    68.57mA    81.6mA     66.54mA
-940mV    54.18mA    65.48mA    52.86mA
-880mV    45.44mA    54.37mA    45.42mA
-840mV    41.37mA    47.76mA    42.54mA
-800mV    38.8mA     42.12mA    40.66mA
-740mV    36.29mA    36.18mA    38.35mA
-660mV    33.55mA    32.19mA    35.5mA
-460mV    27.89mA    26.55mA    29.41mA
675mV     0A         NA         NA
2.7V      0A         0A         0A
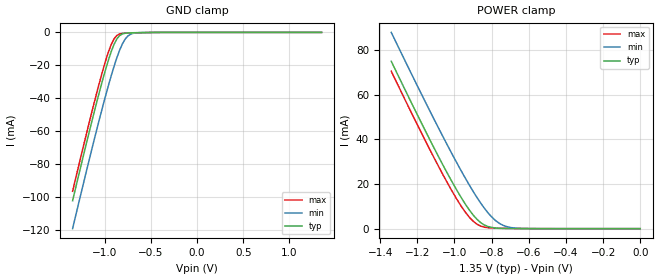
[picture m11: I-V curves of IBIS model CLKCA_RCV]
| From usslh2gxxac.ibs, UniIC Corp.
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|   Model CLKCA_RCV
[Model]  CLKCA_RCV
Model_type Input
Vinl =   0.54000000V
Vinh =   0.81000000V
C_comp   0.8303pF   0.8268pF   0.8502pF
[Temperature Range]   25.0000   95.0000   0.0
[Voltage Range]   1.3500V   1.2830V   1.4500V
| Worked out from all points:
|   GND clamp passes 1 mA (typ) near -0.81 V on its own axis
|   POWER clamp passes 1 mA (typ) near -0.82 V on its own axis
[GND_clamp]
|Voltage   I(typ)   I(min)   I(max)
-1.35V    -102mA     -118.9mA   -96.23mA
-1.11V    -47mA      -63.74mA   -41.31mA
-1.02V    -27.95mA   -44.18mA   -22.52mA
-960mV    -16.49mA   -31.85mA   -11.64mA
-930mV    -11.47mA   -26.01mA   -7.209mA
-900mV    -7.188mA   -20.47mA   -3.873mA
-870mV    -3.95mA    -15.35mA   -1.853mA
-810mV    -922.2uA   -6.956mA   -571.2uA
-750mV    -341.2uA   -2.137mA   -370.4uA
-690mV    -218uA     -531.1uA   -288.8uA
-570mV    -96.46uA   -71.21uA   -157.9uA
1.35V     257.6pA    283.7pA    341.8pA
[POWER_clamp]
|Voltage   I(typ)   I(min)   I(max)
-1.34V    75.01mA    87.96mA    70.55mA
-1.2V     51.1mA     64.07mA    46.64mA
-1.1V     34.59mA    47.45mA    30.21mA
-1.02V    22.06mA    34.59mA    17.87mA
-960mV    13.44mA    25.39mA    9.625mA
-920mV    8.387mA    19.57mA    5.132mA
-880mV    4.308mA    14.14mA    2.067mA
-840mV    1.685mA    9.283mA    678.2uA
-780mV    312.9uA    3.713mA    204.8uA
-720mV    93.05uA    944.1uA    119.2uA
-660mV    42.22uA    183.2uA    74.37uA
0V        257.6pA    218.2pA    466.6pA
